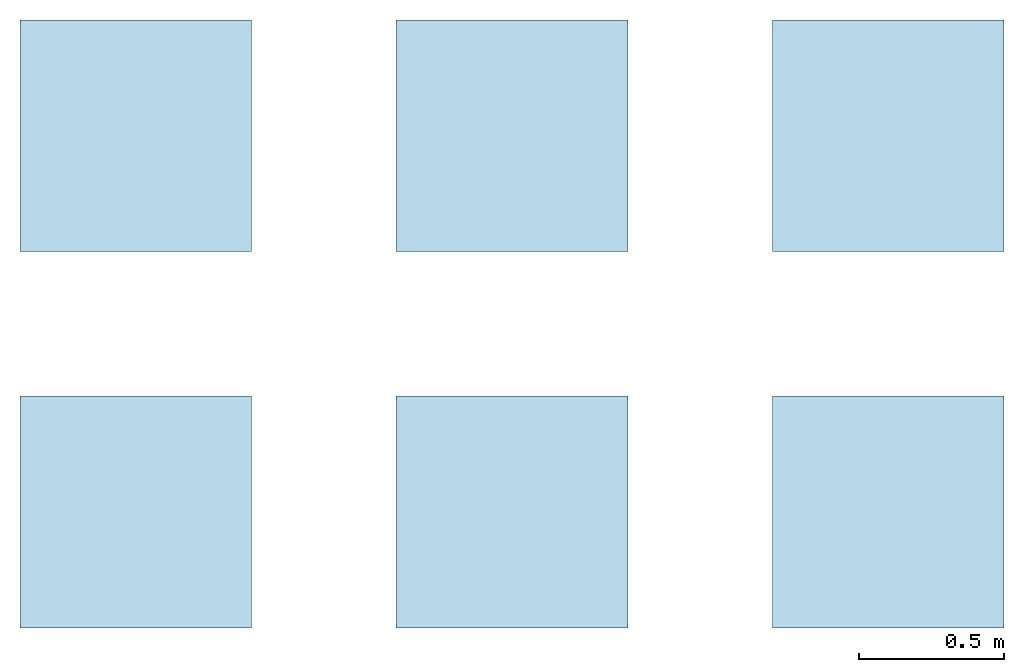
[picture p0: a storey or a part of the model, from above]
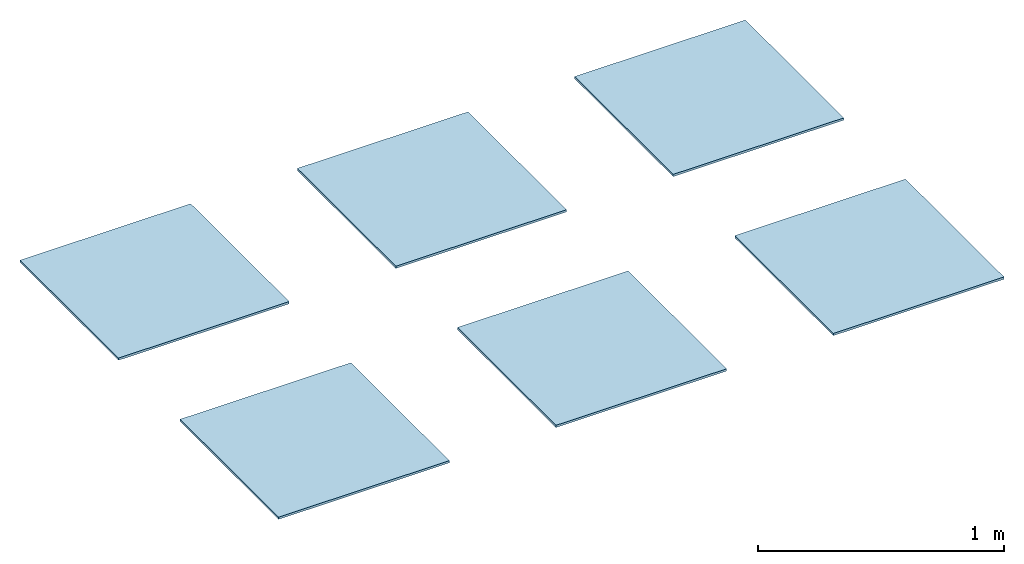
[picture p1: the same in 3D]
Properties of the parts of a building model (IFC2X3)

# File
Description: ViewDefinition [CoordinationView_V2.0]
File name: Número de proyecto
Time: 2017-10-19T11:50:39
Written by: The EXPRESS Data Manager Version 5.02.0100.07 : 28 Aug 2013
Made in: 20160225_1515(x64) - Exporter 17.0.416.0 - Alternate UI 17.12.14.0
Comment: STEP Physical File produced by: The EXPRESS Data Manager Version 5.02.0100.07 : 28 Aug 2013 * Module: EDMstepFileFactory/EDMstandAlone * Creation date: Thu Oct 19 11:50:39 2017 * Host: REVIT * Database: C:\Users\corte\AppData\Local\Temp\{43BBD9A8-B8E7-48FA-B2BC-99AC047D8140}\ifc * Database version: 5507 * Database creation date: Thu Oct 19 11:50:37 2017 * Schema: IFC2X3 * Model: DataRepository.ifc * Model creation date: Thu Oct 19 11:50:37 2017 * Header model: DataRepository.ifc_HeaderModel * Header model creation date: Thu Oct 19 11:50:37 2017 * EDMuser: sdai-user * EDMgroup: sdai-group * License ID and type: 5605 : Permanent license. Expiry date: * EDMstepFileFactory options: 020000

# IfcProject, Número de proyecto
LongName: Nombre de proyecto; Phase: Estado de proyecto

# IfcSite, Default
RefLatitude: 40, 25, 0, 86975; RefLongitude: -3, -42, -1, -243858; RefElevation: 0 m

# IfcBuilding
Pset_BuildingCommon - NumberOfStoreys: 2

# IfcBuildingStorey (2)
Name | LongName | Elevation (m)
LAVERTON FLOOR TILES | LAVERTON FLOOR TILES | 0
Nivel 2 | Nivel 2 | 3

# IfcSlab: Suelo:VIVES LAVERTON-R ARENA 80x80, Suelo:VIVES LAVERTON-R ARENA 80x80:189750
In: LAVERTON FLOOR TILES
PredefinedType: FLOOR; Material: VIVES LAVERTON-R ARENA 80x80 0.011 m
Pset_SlabCommon - Reference: VIVES LAVERTON-R ARENA 80x80; IsExternal: no; LoadBearing: yes; ThermalTransmittance: 136.364 kg/K/s3; PitchAngle: 0 deg
Pset_ManufacturerTypeInformation - Manufacturer: VIVES Azulejos y Gres S.A.

# IfcSlab: Suelo:VIVES LAVERTON-R BEIGE 80x80, Suelo:VIVES LAVERTON-R BEIGE 80x80:212417
In: LAVERTON FLOOR TILES
PredefinedType: FLOOR; Material: VIVES LAVERTON-R BEIGE 80x80 0.011 m
Pset_SlabCommon - IsExternal: no; LoadBearing: yes; PitchAngle: 0 deg; Reference: VIVES LAVERTON-R BEIGE 80x80; ThermalTransmittance: 136.364 kg/K/s3
Pset_ManufacturerTypeInformation - Manufacturer: VIVES Azulejos y Gres S.A.

# IfcSlab: Suelo:VIVES LAVERTON-R GRAFITO 80x80, Suelo:VIVES LAVERTON-R GRAFITO 80x80:212500
In: LAVERTON FLOOR TILES
PredefinedType: FLOOR; Material: VIVES LAVERTON-R GRAFITO 80x80 0.011 m
Pset_SlabCommon - IsExternal: no; LoadBearing: yes; PitchAngle: 0 deg; Reference: VIVES LAVERTON-R GRAFITO 80x80; ThermalTransmittance: 136.364 kg/K/s3
Pset_ManufacturerTypeInformation - Manufacturer: VIVES Azulejos y Gres S.A.

# IfcSlab: Suelo:VIVES LAVERTON-R GRIS 80x80, Suelo:VIVES LAVERTON-R GRIS 80x80:212482
In: LAVERTON FLOOR TILES
PredefinedType: FLOOR; Material: VIVES LAVERTON-R GRIS 80x80 0.011 m
Pset_SlabCommon - IsExternal: no; LoadBearing: yes; PitchAngle: 0 deg; Reference: VIVES LAVERTON-R GRIS 80x80; ThermalTransmittance: 136.364 kg/K/s3
Pset_ManufacturerTypeInformation - Manufacturer: VIVES Azulejos y Gres S.A.

# IfcSlab: Suelo:VIVES LAVERTON-R NATURAL 80x80, Suelo:VIVES LAVERTON-R NATURAL 80x80:212491
In: LAVERTON FLOOR TILES
PredefinedType: FLOOR; Material: VIVES LAVERTON-R NATURAL 80x80 0.011 m
Pset_SlabCommon - IsExternal: no; LoadBearing: yes; PitchAngle: 0 deg; Reference: VIVES LAVERTON-R NATURAL 80x80; ThermalTransmittance: 136.364 kg/K/s3
Pset_ManufacturerTypeInformation - Manufacturer: VIVES Azulejos y Gres S.A.

# IfcSlab: Suelo:VIVES LAVERTON-R NIEVE 80x80, Suelo:VIVES LAVERTON-R NIEVE 80x80:212302
In: LAVERTON FLOOR TILES
PredefinedType: FLOOR; Material: VIVES LAVERTON-R NIEVE 80x80 0.011 m
Pset_SlabCommon - IsExternal: no; LoadBearing: yes; PitchAngle: 0 deg; Reference: VIVES LAVERTON-R NIEVE 80x80; ThermalTransmittance: 136.364 kg/K/s3
Pset_ManufacturerTypeInformation - Manufacturer: VIVES Azulejos y Gres S.A.

# IfcWallStandardCase: Muro básico:VIVES LAVERTON-R ARENA 80x80, Muro básico:VIVES LAVERTON-R ARENA 80x80:204926
In: Nivel 2
Type - PredefinedType: STANDARD; Material: VIVES LAVERTON-R ARENA 80x80 0.011 m
Pset_WallCommon - Reference: VIVES LAVERTON-R ARENA 80x80; IsExternal: no; LoadBearing: no; ExtendToStructure: no; ThermalTransmittance: 136.364 kg/K/s3
Pset_ManufacturerTypeInformation - Manufacturer: VIVES Azulejos y Gres S.A.

# IfcWallStandardCase: Muro básico:VIVES LAVERTON-R BEIGE 80x80, Muro básico:VIVES LAVERTON-R BEIGE 80x80:211908
In: Nivel 2
Type - PredefinedType: STANDARD; Material: VIVES LAVERTON-R BEIGE 80x80 0.011 m
Pset_WallCommon - IsExternal: no; LoadBearing: no; ExtendToStructure: no; Reference: VIVES LAVERTON-R BEIGE 80x80; ThermalTransmittance: 136.364 kg/K/s3
Pset_ManufacturerTypeInformation - Manufacturer: VIVES Azulejos y Gres S.A.

# IfcWallStandardCase: Muro básico:VIVES LAVERTON-R GRAFITO 80x80, Muro básico:VIVES LAVERTON-R GRAFITO 80x80:212050
In: Nivel 2
Type - PredefinedType: STANDARD; Material: VIVES LAVERTON-R GRAFITO 80x80 0.011 m
Pset_WallCommon - IsExternal: no; LoadBearing: no; ExtendToStructure: no; Reference: VIVES LAVERTON-R GRAFITO 80x80; ThermalTransmittance: 136.364 kg/K/s3
Pset_ManufacturerTypeInformation - Manufacturer: VIVES Azulejos y Gres S.A.

# IfcWallStandardCase: Muro básico:VIVES LAVERTON-R GRIS 80x80, Muro básico:VIVES LAVERTON-R GRIS 80x80:212018
In: Nivel 2
Type - PredefinedType: STANDARD; Material: VIVES LAVERTON-R GRIS 80x80 0.011 m
Pset_WallCommon - IsExternal: no; LoadBearing: no; ExtendToStructure: no; Reference: VIVES LAVERTON-R GRIS 80x80; ThermalTransmittance: 136.364 kg/K/s3
Pset_ManufacturerTypeInformation - Manufacturer: VIVES Azulejos y Gres S.A.

# IfcWallStandardCase: Muro básico:VIVES LAVERTON-R NATURAL 80x80, Muro básico:VIVES LAVERTON-R NATURAL 80x80:212034
In: Nivel 2
Type - PredefinedType: STANDARD; Material: VIVES LAVERTON-R NATURAL 80x80 0.011 m
Pset_WallCommon - IsExternal: no; LoadBearing: no; ExtendToStructure: no; Reference: VIVES LAVERTON-R NATURAL 80x80; ThermalTransmittance: 136.364 kg/K/s3
Pset_ManufacturerTypeInformation - Manufacturer: VIVES Azulejos y Gres S.A.

# IfcWallStandardCase: Muro básico:VIVES LAVERTON-R NIEVE 80x80, Muro básico:VIVES LAVERTON-R NIEVE 80x80:211812
In: Nivel 2
Type - PredefinedType: STANDARD; Material: VIVES LAVERTON-R NIEVE 80x80 0.011 m
Pset_WallCommon - IsExternal: no; LoadBearing: no; ExtendToStructure: no; Reference: VIVES LAVERTON-R NIEVE 80x80; ThermalTransmittance: 136.364 kg/K/s3
Pset_ManufacturerTypeInformation - Manufacturer: VIVES Azulejos y Gres S.A.
